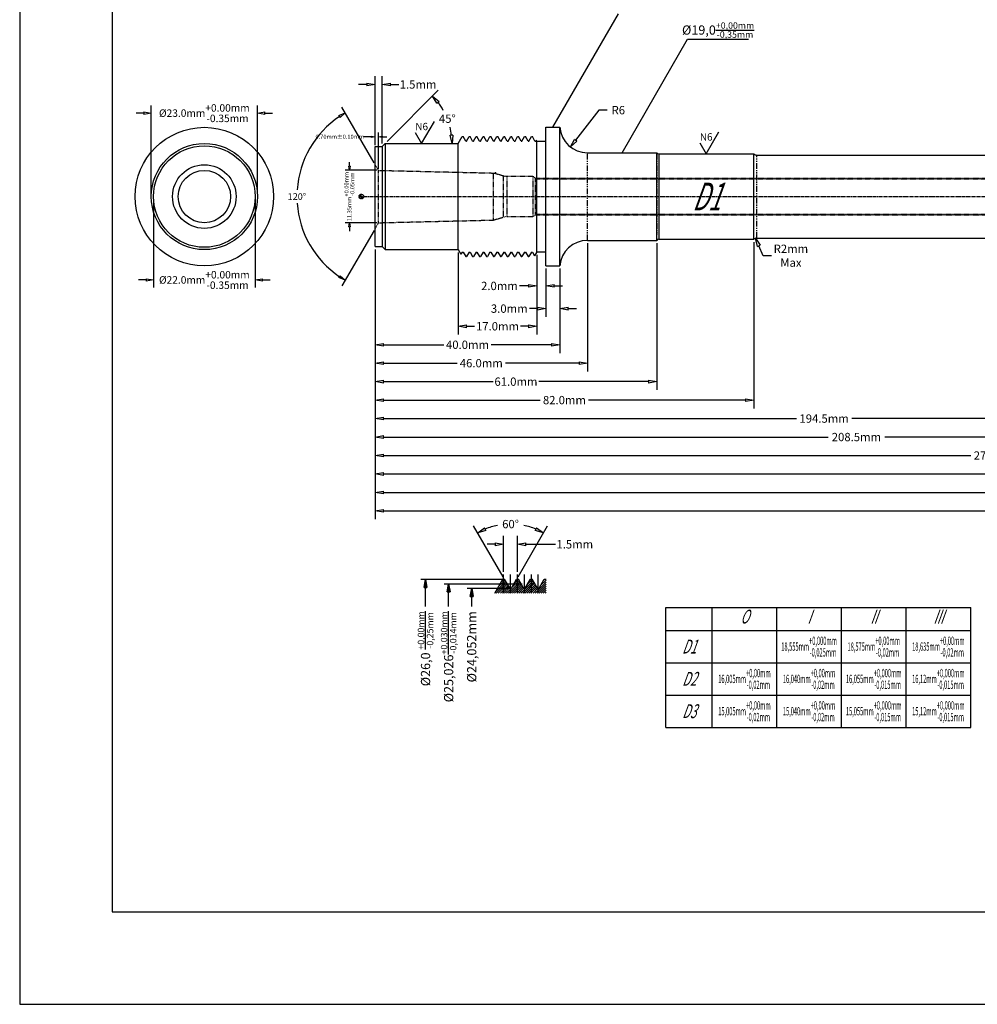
# Model space of a CAD drawing. Units: inches. Extents: x 0 to 594, y 0 to 420.
# Drawn here: x 0 to 207, y 0 to 213 of the extents above; entities that cross this region are included whole.
import ezdxf
from ezdxf.enums import TextEntityAlignment as Align

# ---------------------------------------------------------------- set-up
doc = ezdxf.new("R2010")
doc.units = ezdxf.units.IN
doc.header["$MEASUREMENT"] = 0
for name, pattern in [('CENTER2', [1.125, 0.75, -0.125, 0.125, -0.125]), ('HIDDEN2', [0.1875, 0.125, -0.0625]), ('PHANTOM', [2.5, 1.25, -0.25, 0.25, -0.25, 0.25, -0.25])]:
    doc.linetypes.add(name, pattern=pattern)
for name, color, linetype in [('CENTER', 1, 'CENTER2'), ('CENTERLINE', 1, 'CENTER2'), ('HATCH', 253, 'Continuous'), ('HIDDEN', 5, 'HIDDEN2'), ('PHANTOM', 252, 'PHANTOM'), ('TEXT', 5, 'Continuous')]:
    doc.layers.add(name, color=color, linetype=linetype)
doc.dimstyles.get("Standard").update_dxf_attribs({"dimscale": 10, "dimtxt": 0.18, "dimasz": 0.18, "dimexe": 0.18, "dimexo": 0.0625, "dimgap": 0.09, "dimtad": 0, "dimtih": 1, "dimtoh": 1, "dimdec": 4, "dimzin": 0, "dimdsep": 46, "dimtxsty": 'Standard', "dimblk": 'CLOSEDBLANK', "dimcen": 0.09, "dimadec": 4, "dimazin": 0, "dimtfac": 1, "dimtdec": 4, "dimtofl": 0, "dimtmove": 0, "dimatfit": 3, "dimldrblk": 'CLOSEDBLANK', "dimfxl": 0, "dimtolj": 1, "dimtzin": 0, "dimarcsym": 0})
doc.dimstyles.new('Standard$0', dxfattribs={"dimscale": 10, "dimtxt": 0.18, "dimasz": 0.18, "dimexe": 0.18, "dimexo": 0.0625, "dimgap": 0.09, "dimtad": 0, "dimtih": 1, "dimtoh": 1, "dimdec": 4, "dimzin": 4, "dimdsep": 46, "dimtxsty": 'Standard', "dimblk": 'CLOSEDBLANK', "dimcen": 0.09, "dimadec": 5, "dimazin": 1, "dimtfac": 1, "dimtdec": 4, "dimtofl": 0, "dimtmove": 0, "dimatfit": 3, "dimldrblk": 'CLOSEDBLANK', "dimfxl": 0, "dimtolj": 1, "dimtzin": 0, "dimarcsym": 0})

# ---------------------------------------------------------------- blocks, each defined once
blk = doc.blocks.new('_ClosedBlank')
at = {"color": 0, "linetype": 'ByBlock', "lineweight": -2}
for p, q in [((-1, 0.17), (0, 0)), ((-1, 0.17), (-1, -0.17)), ((0, 0), (-1, -0.17))]:
    blk.add_line(p, q, dxfattribs=at)
blk = doc.blocks.new('*D8')
at = {"color": 0, "lineweight": -2}
for p, q in [((76.1, 187.96), (74.45, 187.96)), ((77, 186.16), (77, 188.86)), ((77.7, 180.99), (77.7, 188.86)), ((78.6, 187.96), (79.5, 187.96))]:
    blk.add_line(p, q, dxfattribs=at)
at = {"layer": 'Defpoints', "color": 0}
for p in [(77.7, 187.96), (77, 185.85), (77.7, 180.68)]:
    blk.add_point(p, dxfattribs=at)
at = {"color": 0, "lineweight": -2, "xscale": 0.8999999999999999, "yscale": 0.8999999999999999, "zscale": 0.8999999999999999}
blk.add_blockref('_ClosedBlank', (77, 187.96), dxfattribs=at)
at = {"color": 0, "lineweight": -2, "xscale": 0.8999999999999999, "yscale": 0.8999999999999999, "zscale": 0.8999999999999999, "rotation": 180}
blk.add_blockref('_ClosedBlank', (77.7, 187.96), dxfattribs=at)
at = {"color": 0, "insert": (69.35, 187.96), "char_height": 0.9, "attachment_point": 5}
blk.add_mtext('\\A1;0.70mm±0.10mm', dxfattribs=at)
blk = doc.blocks.new('*D9')
at = {"color": 0, "lineweight": -2}
for p, q in [((71.42, 181.58), (71.42, 182.48)), ((77.39, 180.68), (70.52, 180.68)), ((77.39, 169.33), (70.52, 169.33)), ((71.42, 168.43), (71.42, 167.53))]:
    blk.add_line(p, q, dxfattribs=at)
at = {"layer": 'Defpoints', "color": 0}
for p in [(71.42, 180.68), (77.7, 180.68), (77.7, 169.33)]:
    blk.add_point(p, dxfattribs=at)
at = {"color": 0, "lineweight": -2, "xscale": 0.8999999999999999, "yscale": 0.8999999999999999, "zscale": 0.8999999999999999}
for p, rotation in [((71.42, 180.68), 270), ((71.42, 169.33), 90)]:
    blk.add_blockref('_ClosedBlank', p, dxfattribs=dict(at, rotation=rotation))
at = {"color": 0, "insert": (71.42, 175), "char_height": 0.9, "attachment_point": 5, "rotation": 90}
blk.add_mtext('\\A1;11.35mm\\S+0.00mm^ -0.05mm;', dxfattribs=at)
blk = doc.blocks.new('*D10')
at = {"color": 0, "lineweight": -2}
for p, q in [((76.75, 182.32), (69.79, 194.37)), ((76.75, 167.68), (69.79, 155.63))]:
    blk.add_line(p, q, dxfattribs=at)
for start, end in [(123.9431, 176.0546), (183.9454, 236.0569)]:
    blk.add_arc((80.98, 175), 20.93, start, end, dxfattribs=at)
at = {"layer": 'Defpoints', "color": 0}
for p in [(61.31, 182.16), (77, 181.89), (77.7, 180.68), (77.7, 169.33), (77, 168.11)]:
    blk.add_point(p, dxfattribs=at)
at = {"color": 0, "lineweight": -2, "xscale": 1.44, "yscale": 1.44, "zscale": 1.44}
for p, rotation in [((70.51, 193.12), 31.97154143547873), ((70.51, 156.88), 328.0284585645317)]:
    blk.add_blockref('_ClosedBlank', p, dxfattribs=dict(at, rotation=rotation))
at = {"color": 0, "insert": (60.05, 175), "char_height": 1.44, "attachment_point": 5}
blk.add_mtext('\\A1;120°', dxfattribs=at)
blk = doc.blocks.new('*D14')
at = {"color": 0, "lineweight": -2}
for p, q in [((77, 186.48), (77, 201.08)), ((78.5, 186.48), (78.5, 201.08)), ((75.2, 199.28), (73.4, 199.28)), ((80.3, 199.28), (82.1, 199.28))]:
    blk.add_line(p, q, dxfattribs=at)
at = {"layer": 'Defpoints', "color": 0}
for p in [(78.5, 199.28), (77, 185.85), (78.5, 185.85)]:
    blk.add_point(p, dxfattribs=at)
at = {"color": 0, "lineweight": -2, "xscale": 1.8, "yscale": 1.8, "zscale": 1.8}
blk.add_blockref('_ClosedBlank', (77, 199.28), dxfattribs=at)
at = {"color": 0, "lineweight": -2, "xscale": 1.8, "yscale": 1.8, "zscale": 1.8, "rotation": 180}
blk.add_blockref('_ClosedBlank', (78.5, 199.28), dxfattribs=at)
at = {"color": 0, "insert": (86.3, 199.28), "char_height": 1.8, "attachment_point": 5}
blk.add_mtext('\\A1;1.5mm', dxfattribs=at)
blk = doc.blocks.new('*D15')
at = {"color": 0, "lineweight": -2}
blk.add_line((79.59, 186.94), (90.68, 198.03), dxfattribs=at)
for start, end in [(29.5981, 37.8873), (7.1127, 14.2286)]:
    blk.add_arc((79.15, 186.5), 14.51, start, end, dxfattribs=at)
at = {"layer": 'Defpoints', "color": 0}
for p in [(91.72, 193.75), (78.5, 185.85), (79.15, 186.5), (79.15, 186.5), (95, 186.5)]:
    blk.add_point(p, dxfattribs=at)
at = {"color": 0, "lineweight": -2, "xscale": 1.8, "yscale": 1.8, "zscale": 1.8}
for p, rotation in [((89.41, 196.76), 131.443631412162), ((93.66, 186.5), 273.5563685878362)]:
    blk.add_blockref('_ClosedBlank', p, dxfattribs=dict(at, rotation=rotation))
at = {"color": 0, "insert": (92.63, 191.87), "char_height": 1.8, "attachment_point": 5}
blk.add_mtext('\\A1;45°', dxfattribs=at)
blk = doc.blocks.new('*D29')
at = {"color": 0, "lineweight": -2}
for p, q in [((125.47, 193.72), (120.41, 187.18)), ((127.27, 193.72), (125.47, 193.72))]:
    blk.add_line(p, q, dxfattribs=at)
at = {"layer": 'Defpoints', "color": 0}
for p in [(122.98, 190.5), (119.31, 185.75)]:
    blk.add_point(p, dxfattribs=at)
at = {"color": 0, "lineweight": -2, "xscale": 1.8, "yscale": 1.8, "zscale": 1.8, "rotation": 232.3171928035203}
blk.add_blockref('_ClosedBlank', (119.31, 185.75), dxfattribs=at)
at = {"color": 0, "insert": (129.67, 193.72), "char_height": 1.8, "attachment_point": 5}
blk.add_mtext('\\A1;R6', dxfattribs=at)
blk = doc.blocks.new('*D31')
at = {"color": 0, "lineweight": -2}
for p, q in [((77, 163.53), (77, 141.09)), ((117, 155.38), (117, 141.09)), ((78.8, 142.89), (91.9, 142.89)), ((115.2, 142.89), (102.1, 142.89))]:
    blk.add_line(p, q, dxfattribs=at)
at = {"layer": 'Defpoints', "color": 0}
for p in [(77, 164.15), (117, 156), (117, 142.89)]:
    blk.add_point(p, dxfattribs=at)
at = {"color": 0, "lineweight": -2, "xscale": 1.8, "yscale": 1.8, "zscale": 1.8, "rotation": 180}
blk.add_blockref('_ClosedBlank', (77, 142.89), dxfattribs=at)
at = {"color": 0, "lineweight": -2, "xscale": 1.8, "yscale": 1.8, "zscale": 1.8}
blk.add_blockref('_ClosedBlank', (117, 142.89), dxfattribs=at)
at = {"color": 0, "insert": (97, 142.89), "char_height": 1.8, "attachment_point": 5}
blk.add_mtext('\\A1;40.0mm', dxfattribs=at)
blk = doc.blocks.new('*D32')
at = {"color": 0, "lineweight": -2}
for p, q in [((122.98, 164.88), (122.98, 137.1)), ((77, 163.53), (77, 137.1)), ((78.8, 138.9), (94.74, 138.9)), ((121.18, 138.9), (105.24, 138.9))]:
    blk.add_line(p, q, dxfattribs=at)
at = {"layer": 'Defpoints', "color": 0}
for p in [(122.98, 165.5), (77, 164.15), (77, 138.9)]:
    blk.add_point(p, dxfattribs=at)
at = {"color": 0, "lineweight": -2, "xscale": 1.8, "yscale": 1.8, "zscale": 1.8, "rotation": 180}
blk.add_blockref('_ClosedBlank', (77, 138.9), dxfattribs=at)
at = {"color": 0, "lineweight": -2, "xscale": 1.8, "yscale": 1.8, "zscale": 1.8}
blk.add_blockref('_ClosedBlank', (122.98, 138.9), dxfattribs=at)
at = {"color": 0, "insert": (99.99, 138.9), "char_height": 1.8, "attachment_point": 5}
blk.add_mtext('\\A1;46.0mm', dxfattribs=at)
blk = doc.blocks.new('*D33')
at = {"color": 0, "lineweight": -2}
for p, q in [((138, 164.88), (138, 133.1)), ((77, 163.53), (77, 133.1)), ((78.8, 134.9), (102.55, 134.9)), ((136.2, 134.9), (112.45, 134.9))]:
    blk.add_line(p, q, dxfattribs=at)
at = {"layer": 'Defpoints', "color": 0}
for p in [(138, 165.5), (77, 164.15), (77, 134.9)]:
    blk.add_point(p, dxfattribs=at)
at = {"color": 0, "lineweight": -2, "xscale": 1.8, "yscale": 1.8, "zscale": 1.8, "rotation": 180}
blk.add_blockref('_ClosedBlank', (77, 134.9), dxfattribs=at)
at = {"color": 0, "lineweight": -2, "xscale": 1.8, "yscale": 1.8, "zscale": 1.8}
blk.add_blockref('_ClosedBlank', (138, 134.9), dxfattribs=at)
at = {"color": 0, "insert": (107.5, 134.9), "char_height": 1.8, "attachment_point": 5}
blk.add_mtext('\\A1;61.0mm', dxfattribs=at)
blk = doc.blocks.new('*D34')
at = {"color": 0, "lineweight": -2}
for p, q in [((159, 165.13), (159, 129.1)), ((77, 163.53), (77, 129.1)), ((78.8, 130.9), (112.75, 130.9)), ((157.2, 130.9), (123.25, 130.9))]:
    blk.add_line(p, q, dxfattribs=at)
at = {"layer": 'Defpoints', "color": 0}
for p in [(159, 165.75), (77, 164.15), (77, 130.9)]:
    blk.add_point(p, dxfattribs=at)
at = {"color": 0, "lineweight": -2, "xscale": 1.8, "yscale": 1.8, "zscale": 1.8, "rotation": 180}
blk.add_blockref('_ClosedBlank', (77, 130.9), dxfattribs=at)
at = {"color": 0, "lineweight": -2, "xscale": 1.8, "yscale": 1.8, "zscale": 1.8}
blk.add_blockref('_ClosedBlank', (159, 130.9), dxfattribs=at)
at = {"color": 0, "insert": (118, 130.9), "char_height": 1.8, "attachment_point": 5}
blk.add_mtext('\\A1;82.0mm', dxfattribs=at)
blk = doc.blocks.new('*D35')
at = {"color": 0, "lineweight": -2}
for p, q in [((271.5, 165.38), (271.5, 125.1)), ((77, 163.53), (77, 125.1)), ((78.8, 126.9), (168.25, 126.9)), ((269.7, 126.9), (180.25, 126.9))]:
    blk.add_line(p, q, dxfattribs=at)
at = {"layer": 'Defpoints', "color": 0}
for p in [(271.5, 166), (77, 164.15), (77, 126.9)]:
    blk.add_point(p, dxfattribs=at)
at = {"color": 0, "lineweight": -2, "xscale": 1.8, "yscale": 1.8, "zscale": 1.8, "rotation": 180}
blk.add_blockref('_ClosedBlank', (77, 126.9), dxfattribs=at)
at = {"color": 0, "lineweight": -2, "xscale": 1.8, "yscale": 1.8, "zscale": 1.8}
blk.add_blockref('_ClosedBlank', (271.5, 126.9), dxfattribs=at)
at = {"color": 0, "insert": (174.25, 126.9), "char_height": 1.8, "attachment_point": 5}
blk.add_mtext('\\A1;194.5mm', dxfattribs=at)
blk = doc.blocks.new('*D36')
at = {"color": 0, "lineweight": -2}
for p, q in [((285.5, 165.39), (285.5, 121.1)), ((77, 163.53), (77, 121.1)), ((78.8, 122.9), (175.1, 122.9)), ((283.7, 122.9), (187.4, 122.9))]:
    blk.add_line(p, q, dxfattribs=at)
at = {"layer": 'Defpoints', "color": 0}
for p in [(285.5, 166.01), (77, 164.15), (77, 122.9)]:
    blk.add_point(p, dxfattribs=at)
at = {"color": 0, "lineweight": -2, "xscale": 1.8, "yscale": 1.8, "zscale": 1.8, "rotation": 180}
blk.add_blockref('_ClosedBlank', (77, 122.9), dxfattribs=at)
at = {"color": 0, "lineweight": -2, "xscale": 1.8, "yscale": 1.8, "zscale": 1.8}
blk.add_blockref('_ClosedBlank', (285.5, 122.9), dxfattribs=at)
at = {"color": 0, "insert": (181.25, 122.9), "char_height": 1.8, "attachment_point": 5}
blk.add_mtext('\\A1;208.5mm', dxfattribs=at)
blk = doc.blocks.new('*D37')
at = {"color": 0, "lineweight": -2}
for p, q in [((347, 166.13), (347, 117.1)), ((77, 163.53), (77, 117.1)), ((78.8, 118.9), (206, 118.9)), ((345.2, 118.9), (218, 118.9))]:
    blk.add_line(p, q, dxfattribs=at)
at = {"layer": 'Defpoints', "color": 0}
for p in [(347, 166.75), (77, 164.15), (77, 118.9)]:
    blk.add_point(p, dxfattribs=at)
at = {"color": 0, "lineweight": -2, "xscale": 1.8, "yscale": 1.8, "zscale": 1.8, "rotation": 180}
blk.add_blockref('_ClosedBlank', (77, 118.9), dxfattribs=at)
at = {"color": 0, "lineweight": -2, "xscale": 1.8, "yscale": 1.8, "zscale": 1.8}
blk.add_blockref('_ClosedBlank', (347, 118.9), dxfattribs=at)
at = {"color": 0, "insert": (212, 118.9), "char_height": 1.8, "attachment_point": 5}
blk.add_mtext('\\A1;270.0mm', dxfattribs=at)
blk = doc.blocks.new('*D38')
at = {"color": 0, "lineweight": -2}
for p, q in [((385, 166.38), (385, 113.1)), ((77, 163.53), (77, 113.1)), ((78.8, 114.9), (225, 114.9)), ((383.2, 114.9), (237, 114.9))]:
    blk.add_line(p, q, dxfattribs=at)
at = {"layer": 'Defpoints', "color": 0}
for p in [(385, 167), (77, 164.15), (77, 114.9)]:
    blk.add_point(p, dxfattribs=at)
at = {"color": 0, "lineweight": -2, "xscale": 1.8, "yscale": 1.8, "zscale": 1.8, "rotation": 180}
blk.add_blockref('_ClosedBlank', (77, 114.9), dxfattribs=at)
at = {"color": 0, "lineweight": -2, "xscale": 1.8, "yscale": 1.8, "zscale": 1.8}
blk.add_blockref('_ClosedBlank', (385, 114.9), dxfattribs=at)
at = {"color": 0, "insert": (231, 114.9), "char_height": 1.8, "attachment_point": 5}
blk.add_mtext('\\A1;308.0mm', dxfattribs=at)
blk = doc.blocks.new('*D39')
at = {"color": 0, "lineweight": -2}
for p, q in [((445, 166.68), (445, 109.1)), ((77, 163.53), (77, 109.1)), ((78.8, 110.9), (254.85, 110.9)), ((443.2, 110.9), (267.15, 110.9))]:
    blk.add_line(p, q, dxfattribs=at)
at = {"layer": 'Defpoints', "color": 0}
for p in [(445, 167.3), (77, 164.15), (77, 110.9)]:
    blk.add_point(p, dxfattribs=at)
at = {"color": 0, "lineweight": -2, "xscale": 1.8, "yscale": 1.8, "zscale": 1.8, "rotation": 180}
blk.add_blockref('_ClosedBlank', (77, 110.9), dxfattribs=at)
at = {"color": 0, "lineweight": -2, "xscale": 1.8, "yscale": 1.8, "zscale": 1.8}
blk.add_blockref('_ClosedBlank', (445, 110.9), dxfattribs=at)
at = {"color": 0, "insert": (261, 110.9), "char_height": 1.8, "attachment_point": 5}
blk.add_mtext('\\A1;368.0mm', dxfattribs=at)
blk = doc.blocks.new('*D40')
at = {"color": 0, "lineweight": -2}
for p, q in [((114, 159.38), (114, 148.92)), ((117, 159.38), (117, 148.92)), ((112.2, 150.72), (110.4, 150.72)), ((118.8, 150.72), (120.6, 150.72))]:
    blk.add_line(p, q, dxfattribs=at)
at = {"layer": 'Defpoints', "color": 0}
for p in [(114, 160), (117, 160), (117, 150.72)]:
    blk.add_point(p, dxfattribs=at)
at = {"color": 0, "lineweight": -2, "xscale": 1.8, "yscale": 1.8, "zscale": 1.8}
blk.add_blockref('_ClosedBlank', (114, 150.72), dxfattribs=at)
at = {"color": 0, "lineweight": -2, "xscale": 1.8, "yscale": 1.8, "zscale": 1.8, "rotation": 180}
blk.add_blockref('_ClosedBlank', (117, 150.72), dxfattribs=at)
at = {"color": 0, "insert": (106.05, 150.72), "char_height": 1.8, "attachment_point": 5}
blk.add_mtext('\\A1;3.0mm', dxfattribs=at)
blk = doc.blocks.new('*D41')
at = {"color": 0, "lineweight": -2}
for p, q in [((492, 168.13), (492, 105.1)), ((77, 163.53), (77, 105.1)), ((78.8, 106.9), (278.65, 106.9)), ((490.2, 106.9), (290.35, 106.9))]:
    blk.add_line(p, q, dxfattribs=at)
at = {"layer": 'Defpoints', "color": 0}
for p in [(492, 168.75), (77, 164.15), (77, 106.9)]:
    blk.add_point(p, dxfattribs=at)
at = {"color": 0, "lineweight": -2, "xscale": 1.8, "yscale": 1.8, "zscale": 1.8, "rotation": 180}
blk.add_blockref('_ClosedBlank', (77, 106.9), dxfattribs=at)
at = {"color": 0, "lineweight": -2, "xscale": 1.8, "yscale": 1.8, "zscale": 1.8}
blk.add_blockref('_ClosedBlank', (492, 106.9), dxfattribs=at)
at = {"color": 0, "insert": (284.5, 106.9), "char_height": 1.8, "attachment_point": 5}
blk.add_mtext('\\A1;415.0mm', dxfattribs=at)
blk = doc.blocks.new('*D42')
at = {"color": 0, "lineweight": -2}
for p, q in [((112, 162.38), (112, 153.84)), ((114, 159.38), (114, 153.84)), ((110.2, 155.64), (108.27, 155.64)), ((115.8, 155.64), (117.6, 155.64))]:
    blk.add_line(p, q, dxfattribs=at)
at = {"layer": 'Defpoints', "color": 0}
for p in [(112, 163), (114, 160), (114, 155.64)]:
    blk.add_point(p, dxfattribs=at)
at = {"color": 0, "lineweight": -2, "xscale": 1.8, "yscale": 1.8, "zscale": 1.8}
blk.add_blockref('_ClosedBlank', (112, 155.64), dxfattribs=at)
at = {"color": 0, "lineweight": -2, "xscale": 1.8, "yscale": 1.8, "zscale": 1.8, "rotation": 180}
blk.add_blockref('_ClosedBlank', (114, 155.64), dxfattribs=at)
at = {"color": 0, "insert": (103.92, 155.64), "char_height": 1.8, "attachment_point": 5}
blk.add_mtext('\\A1;2.0mm', dxfattribs=at)
blk = doc.blocks.new('*D43')
at = {"color": 0, "lineweight": -2}
for p, q in [((95, 162.88), (95, 145.09)), ((112, 162.38), (112, 145.09)), ((96.8, 146.89), (98.55, 146.89)), ((110.2, 146.89), (108.45, 146.89))]:
    blk.add_line(p, q, dxfattribs=at)
at = {"layer": 'Defpoints', "color": 0}
for p in [(95, 163.5), (112, 163), (112, 146.89)]:
    blk.add_point(p, dxfattribs=at)
at = {"color": 0, "lineweight": -2, "xscale": 1.8, "yscale": 1.8, "zscale": 1.8, "rotation": 180}
blk.add_blockref('_ClosedBlank', (95, 146.89), dxfattribs=at)
at = {"color": 0, "lineweight": -2, "xscale": 1.8, "yscale": 1.8, "zscale": 1.8}
blk.add_blockref('_ClosedBlank', (112, 146.89), dxfattribs=at)
at = {"color": 0, "insert": (103.5, 146.89), "char_height": 1.8, "attachment_point": 5}
blk.add_mtext('\\A1;17.0mm', dxfattribs=at)
blk = doc.blocks.new('*D44')
at = {"color": 0, "lineweight": -2}
for p, q in [((161.06, 162.18), (160.1, 164.31)), ((162.86, 162.18), (161.06, 162.18))]:
    blk.add_line(p, q, dxfattribs=at)
at = {"layer": 'Defpoints', "color": 0}
for p in [(159.36, 165.95), (160.18, 164.13)]:
    blk.add_point(p, dxfattribs=at)
at = {"color": 0, "lineweight": -2, "xscale": 1.8, "yscale": 1.8, "zscale": 1.8, "rotation": 114.356826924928}
blk.add_blockref('_ClosedBlank', (159.36, 165.95), dxfattribs=at)
at = {"color": 0, "insert": (167.06, 162.18), "char_height": 1.8, "attachment_point": 5}
blk.add_mtext('\\A1;R2mm\\PMax', dxfattribs=at)
blk = doc.blocks.new('*D57')
at = {"color": 0, "lineweight": -2}
for p, q in [((29, 174.44), (29, 155.31)), ((51, 174.44), (51, 155.31)), ((27.38, 156.93), (25.76, 156.93)), ((52.62, 156.93), (54.24, 156.93))]:
    blk.add_line(p, q, dxfattribs=at)
at = {"layer": 'Defpoints', "color": 0}
for p in [(29, 175), (51, 175), (51, 156.93)]:
    blk.add_point(p, dxfattribs=at)
at = {"color": 0, "lineweight": -2, "xscale": 1.62, "yscale": 1.62, "zscale": 1.62}
blk.add_blockref('_ClosedBlank', (29, 156.93), dxfattribs=at)
at = {"color": 0, "lineweight": -2, "xscale": 1.62, "yscale": 1.62, "zscale": 1.62, "rotation": 180}
blk.add_blockref('_ClosedBlank', (51, 156.93), dxfattribs=at)
at = {"color": 0, "insert": (40, 156.93), "char_height": 1.62, "attachment_point": 5}
blk.add_mtext('\\A1;%%C22.0mm\\S+0.00mm^ -0.35mm;', dxfattribs=at)
blk = doc.blocks.new('*D58')
at = {"color": 0, "lineweight": -2}
for p, q in [((28.5, 175.56), (28.5, 194.69)), ((51.5, 175.56), (51.5, 194.69)), ((26.88, 193.07), (25.26, 193.07)), ((53.12, 193.07), (54.74, 193.07))]:
    blk.add_line(p, q, dxfattribs=at)
at = {"layer": 'Defpoints', "color": 0}
for p in [(51.5, 193.07), (28.5, 175), (51.5, 175)]:
    blk.add_point(p, dxfattribs=at)
at = {"color": 0, "lineweight": -2, "xscale": 1.62, "yscale": 1.62, "zscale": 1.62}
blk.add_blockref('_ClosedBlank', (28.5, 193.07), dxfattribs=at)
at = {"color": 0, "lineweight": -2, "xscale": 1.62, "yscale": 1.62, "zscale": 1.62, "rotation": 180}
blk.add_blockref('_ClosedBlank', (51.5, 193.07), dxfattribs=at)
at = {"color": 0, "insert": (40, 193.07), "char_height": 1.62, "attachment_point": 5}
blk.add_mtext('\\A1;%%C23.0mm\\S+0.00mm^ -0.35mm;', dxfattribs=at)
blk = doc.blocks.new('*D59')
at = {"color": 0, "lineweight": -2}
for p, q in [((104.83, 93.72), (104.83, 101.46)), ((107.83, 93.72), (107.83, 101.46)), ((103.03, 99.66), (101.23, 99.66)), ((109.63, 99.66), (116.04, 99.66))]:
    blk.add_line(p, q, dxfattribs=at)
at = {"layer": 'Defpoints', "color": 0}
for p in [(107.83, 99.66), (104.83, 93.1), (107.83, 93.1)]:
    blk.add_point(p, dxfattribs=at)
at = {"color": 0, "lineweight": -2, "xscale": 1.8, "yscale": 1.8, "zscale": 1.8}
blk.add_blockref('_ClosedBlank', (104.83, 99.66), dxfattribs=at)
at = {"color": 0, "lineweight": -2, "xscale": 1.8, "yscale": 1.8, "zscale": 1.8, "rotation": 180}
blk.add_blockref('_ClosedBlank', (107.83, 99.66), dxfattribs=at)
at = {"color": 0, "insert": (120.24, 99.66), "char_height": 1.8, "attachment_point": 5}
blk.add_mtext('\\A1;1.5mm', dxfattribs=at)
blk = doc.blocks.new('*D60')
at = {"color": 0, "lineweight": -2}
for p, q in [((104.71, 92.64), (98.33, 103.69)), ((107.96, 92.64), (114.34, 103.69))]:
    blk.add_line(p, q, dxfattribs=at)
for start, end in [(101.5653, 112.7402), (67.2598, 78.4347)]:
    blk.add_arc((106.33, 89.83), 14.22, start, end, dxfattribs=at)
at = {"layer": 'Defpoints', "color": 0}
for p in [(108.8, 103.82), (105.02, 92.1), (107.65, 92.1), (106.15, 90.15), (106.52, 90.15)]:
    blk.add_point(p, dxfattribs=at)
at = {"color": 0, "lineweight": -2, "xscale": 1.8, "yscale": 1.8, "zscale": 1.8}
for p, rotation in [((99.23, 102.14), 206.3701175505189), ((113.44, 102.14), 333.6298824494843)]:
    blk.add_blockref('_ClosedBlank', p, dxfattribs=dict(at, rotation=rotation))
at = {"color": 0, "insert": (106.33, 104.04), "char_height": 1.8, "attachment_point": 5}
blk.add_mtext('\\A1;60°', dxfattribs=at)

msp = doc.modelspace()

# ---------------------------------------------------------------- hatches: boundary and pattern name
for points in [[(87.91514, 92.09842), (87.61514, 90.29842), (88.21514, 90.29842)], [(92.91514, 91.12742), (92.61514, 89.32742), (93.21514, 89.32742)], [(97.91514, 90.15042), (97.61514, 88.35042), (98.21514, 88.35042)]]:
    msp.add_hatch(color=256).paths.add_polyline_path(points)
at = {"layer": 'CENTER'}
h = msp.add_hatch(dxfattribs=at)
h.set_pattern_fill('ANSI31', color=256, style=0)
h.set_pattern_definition([(45, (22, 125), (-0.08838835, 0.08838835), [])])
h.paths.add_polyline_path([(74.49996, 175.00003), (73.99996, 175.00003), (73.99996, 174.50003, 0.414213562)])
h.paths.add_polyline_path([(73.99996, 175.50003, 0.414213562), (73.49996, 175.00003), (73.99996, 175.00003)])
at = {"layer": 'HATCH'}
h = msp.add_hatch(dxfattribs=at)
h.set_pattern_fill('ANSI31', color=256, scale=2.5, style=0)
h.set_pattern_definition([(45, (20, 20), (-0.2209709, 0.2209709), [])])
h.paths.add_polyline_path([(104.83469, 92.09842), (104.64719, 92.09842), (104.08658, 91.12742), (104.83469, 91.12742)])
h.paths.add_polyline_path([(105.02219, 92.09842), (104.83469, 92.09842), (104.83469, 91.12742), (105.58279, 91.12742)])
h.paths.add_polyline_path([(105.58279, 91.12742), (104.83469, 91.12742), (104.83469, 90.15042), (106.14687, 90.15042)])
h.paths.add_polyline_path([(104.83469, 91.12742), (104.08658, 91.12742), (103.52251, 90.15042), (104.83469, 90.15042)])
h.paths.add_polyline_path([(104.83469, 90.15042), (103.52251, 90.15042), (102.91514, 89.09842), (104.83469, 89.09842)])
h.paths.add_polyline_path([(106.33469, 90.14987), (106.14719, 90.14987), (106.14687, 90.15042), (104.83469, 90.15042), (104.83469, 89.09842), (106.33469, 89.09842)])
h.paths.add_polyline_path([(107.83469, 91.12742), (107.08658, 91.12742), (106.52219, 90.14987), (106.33469, 90.14987), (106.33469, 89.09842), (107.83469, 89.09842)])
h.paths.add_polyline_path([(107.83469, 92.09842), (107.64719, 92.09842), (107.08658, 91.12742), (107.83469, 91.12742)])
h.paths.add_polyline_path([(108.02219, 92.09842), (107.83469, 92.09842), (107.83469, 91.12742), (108.58279, 91.12742)])
h.paths.add_polyline_path([(108.58279, 91.12742), (107.83469, 91.12742), (107.83469, 89.09842), (109.33469, 89.09842), (109.33469, 90.14987), (109.14719, 90.14987)])
h.paths.add_polyline_path([(110.83469, 92.09842), (110.64719, 92.09842), (109.52219, 90.14987), (109.33469, 90.14987), (109.33469, 89.09842), (110.83469, 89.09842)])
h.paths.add_polyline_path([(112.33469, 90.14987), (112.14719, 90.14987), (111.02219, 92.09842), (110.83469, 92.09842), (110.83469, 89.09842), (112.33469, 89.09842)])
h.paths.add_polyline_path([(114.02219, 92.09842), (113.64719, 92.09842), (112.52219, 90.14987), (112.33469, 90.14987), (112.33469, 89.09842), (114.02219, 89.09842)])

# ---------------------------------------------------------------- linework, layer by layer
for p, q in [((115.49996, 190.00003), (129.68855, 214.57538)), ((130.48952, 184.50003), (144.67811, 209.07538)), ((144.67811, 209.07538), (157.89967, 209.07538)), ((87.07496, 186.50003), (89.82459, 191.26253)), ((113.99996, 160.00003), (113.99996, 190.00003)), ((113.99996, 190.00003), (116.99996, 190.00003)), ((116.99996, 160.00003), (116.99996, 190.00003)), ((85.70014, 188.88128), (87.07496, 186.50003)), ((94.99996, 186.50003), (95.86599, 188.00003)), ((95.86599, 188.00003), (96.05349, 188.00003)), ((96.61599, 187.02575), (96.05349, 188.00003)), ((96.80349, 187.02575), (97.36599, 188.00003)), ((97.36599, 188.00003), (97.55349, 188.00003)), ((98.11599, 187.02575), (97.55349, 188.00003)), ((98.30349, 187.02575), (98.86599, 188.00003)), ((98.86599, 188.00003), (99.05349, 188.00003)), ((99.61599, 187.02575), (99.05349, 188.00003)), ((99.80349, 187.02575), (100.36599, 188.00003)), ((100.36599, 188.00003), (100.55349, 188.00003)), ((101.11599, 187.02575), (100.55349, 188.00003)), ((101.30349, 187.02575), (101.86599, 188.00003)), ((101.86599, 188.00003), (102.05349, 188.00003)), ((102.61599, 187.02575), (102.05349, 188.00003)), ((102.80349, 187.02575), (103.36599, 188.00003)), ((103.36599, 188.00003), (103.55349, 188.00003)), ((104.11599, 187.02575), (103.55349, 188.00003)), ((104.30349, 187.02575), (104.86599, 188.00003)), ((104.86599, 188.00003), (105.05349, 188.00003)), ((105.61599, 187.02575), (105.05349, 188.00003)), ((105.80349, 187.02575), (106.36599, 188.00003)), ((106.36599, 188.00003), (106.55349, 188.00003)), ((107.11599, 187.02575), (106.55349, 188.00003)), ((107.30349, 187.02575), (107.86599, 188.00003)), ((107.86599, 188.00003), (108.05349, 188.00003)), ((108.61599, 187.02575), (108.05349, 188.00003)), ((108.80349, 187.02575), (109.36599, 188.00003)), ((109.36599, 188.00003), (109.55349, 188.00003)), ((110.11599, 187.02575), (109.55349, 188.00003)), ((110.30349, 187.02575), (110.86599, 188.00003)), ((110.86599, 188.00003), (111.05349, 188.00003)), ((111.61599, 187.02575), (111.05349, 188.00003)), ((148.71647, 184.25003), (151.4661, 189.01253)), ((76.99996, 185.85003), (78.49996, 185.85003)), ((76.99996, 164.15003), (76.99996, 185.85003)), ((78.49996, 185.85003), (79.14996, 186.50003)), ((78.49996, 185.85003), (78.49996, 164.15003)), ((79.14996, 186.50003), (79.14996, 163.50003)), ((79.14996, 186.50003), (94.99996, 186.50003)), ((91.99996, 186.50003), (94.99996, 186.50003)), ((94.99996, 163.46503), (94.99996, 186.50003)), ((94.99996, 163.50003), (94.99996, 186.50003)), ((96.61599, 187.02575), (96.80349, 187.02575)), ((98.11599, 187.02575), (98.30349, 187.02575)), ((99.61599, 187.02575), (99.80349, 187.02575)), ((101.11599, 187.02575), (101.30349, 187.02575)), ((102.61599, 187.02575), (102.80349, 187.02575)), ((104.11599, 187.02575), (104.30349, 187.02575)), ((105.61599, 187.02575), (105.80349, 187.02575)), ((107.11599, 187.02575), (107.30349, 187.02575)), ((108.61599, 187.02575), (108.80349, 187.02575)), ((110.11599, 187.02575), (110.30349, 187.02575)), ((111.61599, 187.02575), (111.80349, 187.02575)), ((111.80349, 187.02575), (111.8943, 187.18304)), ((111.99996, 187.00003), (111.8943, 187.18304)), ((111.99996, 163.00003), (111.99996, 187.00003)), ((111.99996, 187.00003), (113.99996, 187.00003)), ((147.34165, 186.63128), (148.71647, 184.25003)), ((122.97909, 184.50003), (137.99996, 184.50003)), ((137.99996, 165.50003), (137.99996, 184.50003)), ((138.43297, 184.25003), (158.99996, 184.25003)), ((138.43297, 184.25003), (138.43297, 165.75003)), ((158.99996, 165.75003), (158.99996, 184.25003)), ((159.6614, 184.00003), (271.49996, 184.00003)), ((122.97909, 165.50003), (137.99996, 165.50003)), ((138.43297, 165.75003), (158.99996, 165.75003)), ((159.6614, 166.00003), (271.49996, 166.00003)), ((76.99996, 164.15003), (78.49996, 164.15003)), ((78.49996, 164.15003), (79.14996, 163.50003)), ((79.14996, 163.50003), (94.99996, 163.50003)), ((91.99996, 163.50003), (94.99996, 163.50003)), ((94.99996, 163.50003), (95.58474, 162.48717)), ((95.86599, 162.97431), (95.58474, 162.48717)), ((95.86599, 162.97431), (96.05349, 162.97431)), ((96.05349, 162.97431), (96.61599, 162.00003)), ((97.36599, 162.97431), (96.80349, 162.00003)), ((97.36599, 162.97431), (97.55349, 162.97431)), ((97.55349, 162.97431), (98.11599, 162.00003)), ((98.86599, 162.97431), (98.30349, 162.00003)), ((98.86599, 162.97431), (99.05349, 162.97431)), ((99.05349, 162.97431), (99.61599, 162.00003)), ((100.36599, 162.97431), (99.80349, 162.00003)), ((100.36599, 162.97431), (100.55349, 162.97431)), ((100.55349, 162.97431), (101.11599, 162.00003)), ((101.86599, 162.97431), (101.30349, 162.00003)), ((101.86599, 162.97431), (102.05349, 162.97431)), ((102.05349, 162.97431), (102.61599, 162.00003)), ((103.36599, 162.97431), (102.80349, 162.00003)), ((103.36599, 162.97431), (103.55349, 162.97431)), ((103.55349, 162.97431), (104.11599, 162.00003)), ((104.86599, 162.97431), (104.30349, 162.00003)), ((104.86599, 162.97431), (105.05349, 162.97431)), ((105.05349, 162.97431), (105.61599, 162.00003)), ((106.36599, 162.97431), (105.80349, 162.00003)), ((106.36599, 162.97431), (106.55349, 162.97431)), ((106.55349, 162.97431), (107.11599, 162.00003)), ((107.86599, 162.97431), (107.30349, 162.00003)), ((107.86599, 162.97431), (108.05349, 162.97431)), ((108.05349, 162.97431), (108.61599, 162.00003)), ((109.36599, 162.97431), (108.80349, 162.00003)), ((109.36599, 162.97431), (109.55349, 162.97431)), ((109.55349, 162.97431), (110.11599, 162.00003)), ((110.86599, 162.97431), (110.30349, 162.00003)), ((110.86599, 162.97431), (111.05349, 162.97431)), ((111.05349, 162.97431), (111.5193, 162.1675)), ((111.99996, 163.00003), (111.5193, 162.1675)), ((111.99996, 163.00003), (113.99996, 163.00003)), ((96.61599, 162.00003), (96.80349, 162.00003)), ((98.11599, 162.00003), (98.30349, 162.00003)), ((99.61599, 162.00003), (99.80349, 162.00003)), ((101.11599, 162.00003), (101.30349, 162.00003)), ((102.61599, 162.00003), (102.80349, 162.00003)), ((104.11599, 162.00003), (104.30349, 162.00003)), ((105.61599, 162.00003), (105.80349, 162.00003)), ((107.11599, 162.00003), (107.30349, 162.00003)), ((108.61599, 162.00003), (108.80349, 162.00003)), ((110.11599, 162.00003), (110.30349, 162.00003)), ((113.99996, 160.00003), (116.99996, 160.00003)), ((86.91514, 92.09842), (104.64719, 92.09842)), ((87.91514, 86.15042), (87.91514, 92.09842)), ((102.91514, 89.09842), (104.64719, 92.09842)), ((104.64719, 92.09842), (105.02219, 92.09842)), ((104.83469, 89.09842), (104.83469, 93.09842)), ((106.14719, 90.14987), (105.02219, 92.09842)), ((106.33469, 89.09842), (106.33469, 93.09842)), ((106.52219, 90.14987), (107.64719, 92.09842)), ((107.64719, 92.09842), (108.02219, 92.09842)), ((107.83469, 89.09842), (107.83469, 93.09842)), ((109.14719, 90.14987), (108.02219, 92.09842)), ((109.33469, 89.09842), (109.33469, 93.09842)), ((109.52219, 90.14987), (110.64719, 92.09842)), ((110.64719, 92.09842), (111.02219, 92.09842)), ((110.83469, 89.09842), (110.83469, 93.09842)), ((112.14719, 90.14987), (111.02219, 92.09842)), ((112.33469, 89.09842), (112.33469, 93.09842)), ((112.52219, 90.14987), (113.64719, 92.09842)), ((113.64719, 92.09842), (114.02219, 92.09842)), ((91.91514, 91.12742), (108.83469, 91.12742)), ((92.91514, 86.15042), (92.91514, 91.12742)), ((96.91514, 90.15042), (106.14687, 90.15042)), ((97.91514, 86.15042), (97.91514, 90.15042)), ((106.14719, 90.14987), (106.52219, 90.14987)), ((109.14719, 90.14987), (109.52219, 90.14987)), ((112.14719, 90.14987), (112.52219, 90.14987)), ((139.99997, 59.99999), (139.99997, 85.99999)), ((139.99997, 85.99999), (205.99997, 85.99999)), ((149.99997, 59.99999), (149.99997, 85.99999)), ((163.99997, 59.99999), (163.99997, 85.99999)), ((177.99997, 59.99999), (177.99997, 85.99999)), ((191.99997, 59.99999), (191.99997, 85.99999)), ((205.99997, 59.99999), (205.99997, 85.99999)), ((139.99997, 80.99999), (205.99997, 80.99999)), ((139.99997, 73.99999), (205.99997, 73.99999)), ((139.99997, 66.99999), (205.99997, 66.99999)), ((139.99997, 59.99999), (205.99997, 59.99999))]:
    msp.add_line(p, q)
for points in [[(0, 0), (594, 0), (594, 420), (0, 420)], [(20, 20), (574, 20), (574, 400), (20, 400)]]:
    msp.add_lwpolyline(points, close=True)
for radius in [15, 11.5, 11, 6.88745, 5.67502]:
    msp.add_circle((40, 175.00003), radius)
for centre, radius, start, end in [((122.97909, 190.50003), 6, 184.7801918, 270), ((138.43297, 184.75003), 0.5, 210, 270), ((159.6614, 185.00003), 1, 228.5903779, 270), ((122.97909, 159.50003), 6, 90, 175.2198082), ((138.43297, 165.25003), 0.5, 90, 150), ((159.6614, 165.00003), 1, 90, 131.4096221)]:
    msp.add_arc(centre, radius, start, end)
at = {"layer": 'CENTER'}
msp.add_line((73.99996, 174.50003), (73.99996, 175.50003), dxfattribs=at)
msp.add_circle((73.99996, 175.00003), 0.5, dxfattribs=at)
at = {"layer": 'CENTERLINE'}
msp.add_line((73.49996, 175.00003), (493.99996, 175.00003), dxfattribs=at)
at = {"layer": 'HIDDEN'}
for p, q in [((77.69996, 180.67505), (76.99996, 181.88748)), ((77.69996, 180.67505), (102.66907, 180.08969)), ((77.69996, 169.32501), (77.69996, 180.67505)), ((102.66907, 170.04785), (102.66907, 180.13554)), ((102.66907, 180.13554), (104.78483, 179.51351)), ((104.78483, 170.66989), (104.78483, 179.51351)), ((105.63101, 179.3917), (111.24493, 179.3917)), ((105.63101, 170.7917), (105.63101, 179.3917)), ((111.24493, 170.7917), (111.24493, 179.3917)), ((111.24493, 179.3917), (111.7349, 178.90173)), ((111.5825, 178.96243), (490.76571, 178.96243)), ((111.7349, 178.81003), (489.99996, 178.81003)), ((111.73496, 171.28173), (111.73496, 178.90173)), ((105.63101, 170.65415), (111.24493, 170.65415)), ((111.24493, 170.65415), (111.73496, 171.14418)), ((111.58256, 171.03763), (490.76571, 171.03763)), ((111.73496, 171.19003), (489.99996, 171.19003)), ((77.69996, 169.32501), (76.99996, 168.11258)), ((77.69996, 169.32501), (102.66907, 169.91037)), ((102.66907, 169.9103), (104.78483, 170.53234))]:
    msp.add_line(p, q, dxfattribs=at)
for centre, start, end in [((105.63101, 182.3917), 253.6167, 270), ((105.63101, 167.65415), 90, 106.3833)]:
    msp.add_arc(centre, 3, start, end, dxfattribs=at)
msp.add_point((103.04493, 180.12673), dxfattribs=at)
at = {"layer": 'PHANTOM'}
for p, q in [((122.97909, 165.50003), (122.97909, 184.50003)), ((137.99996, 184.25003), (137.99996, 166.70003)), ((159.6614, 166.00003), (159.6614, 184.00003))]:
    msp.add_line(p, q, dxfattribs=at)

# ---------------------------------------------------------------- block references
at = {"xscale": 1.800000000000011, "yscale": 1.800000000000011, "zscale": 1.8, "rotation": 90}
for p in [(87.91514, 92.09842), (92.91514, 91.12742), (97.91514, 90.15042)]:
    msp.add_blockref('_ClosedBlank', p, dxfattribs=at)

# ---------------------------------------------------------------- texts
for p in [(87.07496, 188.88128), (148.71647, 186.63128)]:
    msp.add_text('N6', height=1.5875).set_placement(p, align=Align.BOTTOM_CENTER)
at = {"attachment_point": 5}
for s, insert, char_height, width in [('\\A1;%%C19,0{\\H0.7x;\\S+0,00mm/-0,35mm;}', (151.28889, 211.07538), 2, 19.3721774), ('{\\fArial|b0|i0|c0|p34;\\Q20;\\W0.6;D1}', (148.71647, 175.00003), 6, 8.9342302), ('{\\fArial|b0|i0|c0|p34;\\Q20;\\W0.6;O}', (156.99997, 83.99999), 3, 4.4671151), ('{\\fArial|b0|i0|c0|p34;\\Q20;\\W0.6;I}', (170.99997, 83.99999), 3, 4.4671151), ('{\\fArial|b0|i0|c0|p34;\\Q20;\\W0.6;II}', (184.99997, 83.99999), 3, 4.4671151), ('{\\fArial|b0|i0|c0|p34;\\Q20;\\W0.6;III}', (198.99997, 83.99999), 3, 4.4671151), ('{\\fArial|b0|i0|c0|p34;\\Q20;\\W0.6;D1}', (144.99997, 77.49999), 3, 4.4671151), ('{\\fArial|b0|i0|c0|p34;\\Q20;\\W0.6;D2}', (144.99997, 70.49999), 3, 4.4671151), ('{\\fArial|b0|i0|c0|p34;\\Q20;\\W0.6;D3}', (144.99997, 63.49999), 3, 4.4671151)]:
    msp.add_mtext(s, dxfattribs=dict(at, insert=insert, char_height=char_height, width=width))
at = {"char_height": 1.8, "attachment_point": 5}
for s, insert in [('\\A1;{\\W0.5;18,555mm\\S+0,000mm^ -0,025mm;}', (170.99997, 77.49999)), ('\\A1;{\\W0.5;18,575mm\\S+0,00mm^ -0,02mm;}', (184.99997, 77.49999)), ('\\A1;{\\W0.5;18,635mm\\S+0,00mm^ -0,02mm;}', (198.99997, 77.49999)), ('\\A1;{\\W0.5;16,005mm\\S+0,00mm^ -0,02mm;}', (156.99997, 70.49999)), ('\\A1;{\\W0.5;16,040mm\\S+0,00mm^ -0,02mm;}', (170.99997, 70.49999)), ('\\A1;{\\W0.5;16,055mm\\S+0,000mm^ -0,015mm;}', (184.99997, 70.49999)), ('\\A1;{\\W0.5;16,12mm\\S+0,000mm^ -0,015mm;}', (198.99997, 70.49999)), ('\\A1;{\\W0.5;15,005mm\\S+0,00mm^ -0,02mm;}', (156.99997, 63.49999)), ('\\A1;{\\W0.5;15,040mm\\S+0,00mm^ -0,02mm;}', (170.99997, 63.49999)), ('\\A1;{\\W0.5;15,055mm\\S+0,000mm^ -0,015mm;}', (184.99997, 63.49999)), ('\\A1;{\\W0.5;15,12mm\\S+0,000mm^ -0,015mm;}', (198.99997, 63.49999))]:
    msp.add_mtext(s, dxfattribs=dict(at, insert=insert))
at = {"layer": 'TEXT', "color": 7, "char_height": 2, "attachment_point": 6, "rotation": 90}
for s, insert, width in [('\\A1;%%C26,0 {\\H0.7x;\\S+0,00mm/-0,25mm;}', (87.91514, 85.15042), 20.2415142), ('\\A1;%%C25,026{\\H0.7x;\\S+0,030mm/-0,014mm;}', (92.91514, 85.15042), 24.5501172), ('\\A1;%%C24,052mm', (97.91514, 85.15042), 20.2415142)]:
    msp.add_mtext(s, dxfattribs=dict(at, insert=insert, width=width))

# ---------------------------------------------------------------- dimensions: what is measured, and where the dimension line sits
for base, p1, p2, picture, middle in [((78.49996, 199.28005), (76.99996, 185.85003), (78.49996, 185.85003), '*D14', (86.29996, 199.28005)), ((76.99996, 106.89501), (491.99996, 168.75003), (76.99996, 164.15003), '*D41', (284.49996, 106.89501)), ((76.99996, 110.89501), (444.99996, 167.30003), (76.99996, 164.15003), '*D39', (260.99996, 110.89501)), ((76.99996, 114.89501), (384.99996, 167.00003), (76.99996, 164.15003), '*D38', (230.99996, 114.89501)), ((76.99996, 118.89501), (346.99996, 166.75003), (76.99996, 164.15003), '*D37', (211.99996, 118.89501)), ((76.99996, 122.89501), (285.49996, 166.01003), (76.99996, 164.15003), '*D36', (181.24996, 122.89501)), ((76.99996, 126.89501), (271.49996, 166.00003), (76.99996, 164.15003), '*D35', (174.24996, 126.89501)), ((76.99996, 130.89501), (158.99996, 165.75003), (76.99996, 164.15003), '*D34', (117.99996, 130.89501)), ((76.99996, 138.89501), (122.97909, 165.50003), (76.99996, 164.15003), '*D32', (99.98953, 138.89501)), ((76.99996, 134.89501), (137.99996, 165.50003), (76.99996, 164.15003), '*D33', (107.49996, 134.89501)), ((116.99996, 142.88501), (76.99996, 164.15003), (116.99996, 156.00003), '*D31', (96.99996, 142.88501)), ((111.99996, 146.88501), (94.99996, 163.50003), (111.99996, 163.00003), '*D43', (103.49996, 146.88501))]:
    dim = msp.add_linear_dim(base=base, p1=p1, p2=p2, dimstyle='Standard$0', override={"dimscale": 10, "dimdec": 1, "dimpost": 'mm', "dimblk1": 'ClosedBlank', "dimblk2": 'ClosedBlank', "dimsah": 1})
    dim.commit()
    dim.dimension.update_dxf_attribs({"geometry": picture, "text_midpoint": middle})
for base, line1, line2, picture, middle in [((91.71512, 193.75453), ((79.14996, 186.50003), (94.99996, 186.50003)), ((78.49996, 185.85003), (79.14996, 186.50003)), '*D15', (92.63013, 191.86621)), ((108.80319, 103.82467), ((106.52219, 90.14987), (107.64719, 92.09842)), ((106.14719, 90.14987), (105.02219, 92.09842)), '*D60', (106.33469, 104.04064))]:
    dim = msp.add_angular_dim_2l(base=base, line1=line1, line2=line2, dimstyle='Standard', override={"dimadec": 0})
    dim.commit()
    dim.dimension.update_dxf_attribs({"geometry": picture, "text_midpoint": middle, "dimtype": 162})
for base, p1, p2, picture, middle in [((51.5, 193.06911), (28.5, 175.00003), (51.5, 175.00003), '*D58', (40, 193.06911)), ((51, 156.93095), (29, 175.00003), (51, 175.00003), '*D57', (40, 156.93095))]:
    dim = msp.add_linear_dim(base=base, p1=p1, p2=p2, text='%%C<>', dimstyle='Standard$0', override={"dimscale": 9, "dimdec": 1, "dimpost": 'mm', "dimtol": 1, "dimtm": 0.35, "dimtdec": 2})
    dim.commit()
    dim.dimension.update_dxf_attribs({"geometry": picture, "text_midpoint": middle})
dim = msp.add_angular_dim_2l(base=(61.31022, 182.15795), line1=((77.69996, 180.67505), (76.99996, 181.88748)), line2=((77.69996, 169.32501), (76.99996, 168.11258)), dimstyle='Standard', override={"dimscale": 8, "dimadec": 0})
dim.commit()
dim.dimension.update_dxf_attribs({"geometry": '*D10', "text_midpoint": (60.04809, 175.00003)})
dim = msp.add_radius_dim(center=(122.97909, 190.50003), mpoint=(119.31135, 185.75159), dimstyle='Standard', override={"dimdec": 0, "dimtmove": 1})
dim.commit()
dim.dimension.update_dxf_attribs({"geometry": '*D29', "text_midpoint": (125.46811, 193.72244), "dimtype": 164})
for base, p1, p2, override, picture, middle in [((77.69996, 187.95885), (76.99996, 185.85003), (77.69996, 180.67505), {"dimscale": 5, "dimgap": 0.09, "dimdec": 2, "dimzin": 0, "dimpost": 'mm', "dimblk1": 'ClosedBlank', "dimblk2": 'ClosedBlank', "dimsah": 1, "dimtol": 1, "dimlim": 0, "dimtp": 0.1, "dimtm": 0.1, "dimtdec": 2}, '*D8', (69.35048, 187.95885)), ((113.99996, 155.64203), (111.99996, 163.00003), (113.99996, 160.00003), {"dimscale": 10, "dimdec": 1, "dimpost": 'mm', "dimblk1": 'ClosedBlank', "dimblk2": 'ClosedBlank', "dimsah": 1}, '*D42', (103.91785, 155.64203)), ((116.99996, 150.72001), (113.99996, 160.00003), (116.99996, 160.00003), {"dimscale": 10, "dimdec": 1, "dimpost": 'mm', "dimblk1": 'ClosedBlank', "dimblk2": 'ClosedBlank', "dimsah": 1}, '*D40', (106.04996, 150.72001)), ((107.83469, 99.65831), (104.83469, 93.09842), (107.83469, 93.09842), {"dimdec": 1, "dimlfac": 0.5, "dimpost": 'mm'}, '*D59', (120.24251, 99.65831))]:
    dim = msp.add_linear_dim(base=base, p1=p1, p2=p2, dimstyle='Standard$0', override=override)
    dim.commit()
    dim.dimension.update_dxf_attribs({"geometry": picture, "text_midpoint": middle, "dimtype": 160})
dim = msp.add_linear_dim(base=(71.41508, 180.67505), p1=(77.69996, 169.32501), p2=(77.69996, 180.67505), angle=90, dimstyle='Standard$0', override={"dimscale": 5, "dimdec": 2, "dimpost": 'mm', "dimtol": 1, "dimtm": 0.05, "dimtdec": 2})
dim.commit()
dim.dimension.update_dxf_attribs({"geometry": '*D9', "text_midpoint": (71.41508, 175.00003), "dimtype": 160, "text_rotation": 90})
dim = msp.add_radius_dim(center=(160.18162, 164.13052), mpoint=(159.35678, 165.9525), text='<>\\PMax', dimstyle='Standard', override={"dimscale": 10, "dimdec": 0, "dimpost": 'mm', "dimblk2": 'ClosedBlank', "dimsah": 1, "dimtmove": 1})
dim.commit()
dim.dimension.update_dxf_attribs({"geometry": '*D44', "text_midpoint": (161.06498, 162.17925), "dimtype": 164})

doc.saveas('drawing.dxf')
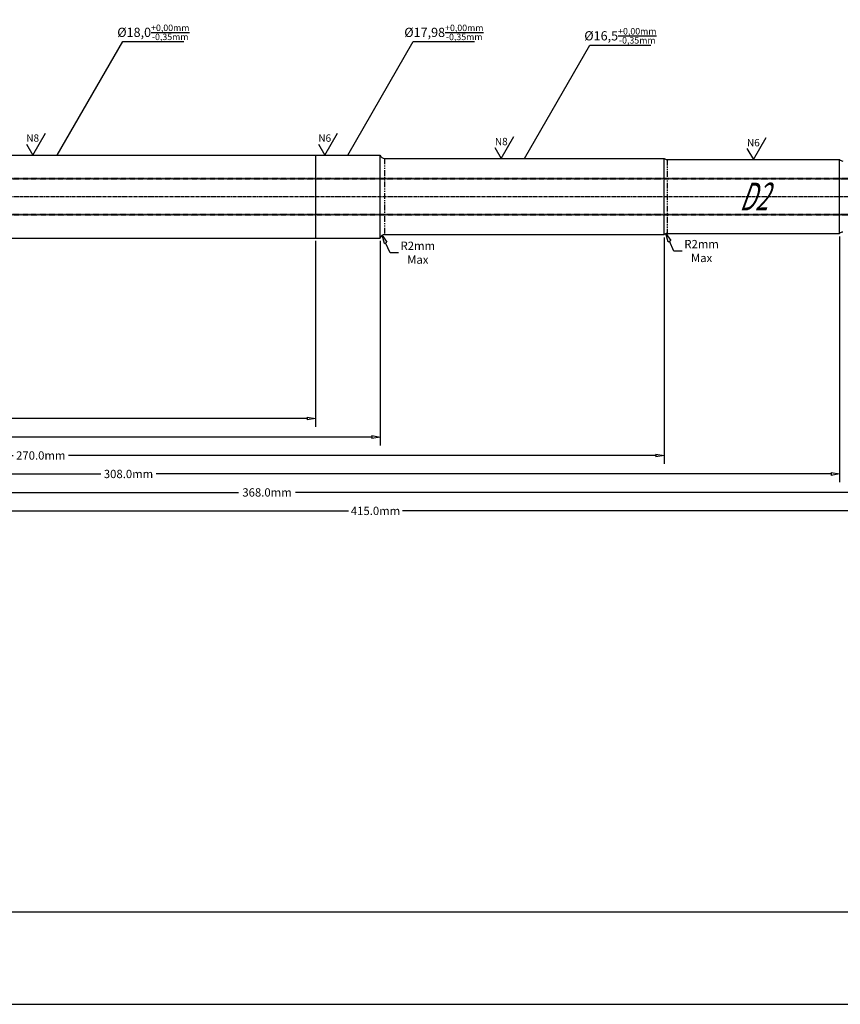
# Model space of a CAD drawing. Units: inches. Extents: x 0 to 594, y 0 to 420.
# Drawn here: x 207 to 385, y 0 to 213 of the extents above; entities that cross this region are included whole.
import ezdxf
from ezdxf.enums import TextEntityAlignment as Align

# ---------------------------------------------------------------- set-up
doc = ezdxf.new("R2010")
doc.units = ezdxf.units.IN
doc.header["$MEASUREMENT"] = 0
for name, pattern in [('CENTER2', [1.125, 0.75, -0.125, 0.125, -0.125]), ('HIDDEN2', [0.1875, 0.125, -0.0625]), ('PHANTOM', [2.5, 1.25, -0.25, 0.25, -0.25, 0.25, -0.25])]:
    doc.linetypes.add(name, pattern=pattern)
for name, color, linetype in [('CENTERLINE', 1, 'CENTER2'), ('HIDDEN', 5, 'HIDDEN2'), ('PHANTOM', 252, 'PHANTOM')]:
    doc.layers.add(name, color=color, linetype=linetype)
doc.dimstyles.get("Standard").update_dxf_attribs({"dimscale": 10, "dimtxt": 0.18, "dimasz": 0.18, "dimexe": 0.18, "dimexo": 0.0625, "dimgap": 0.09, "dimtad": 0, "dimtih": 1, "dimtoh": 1, "dimdec": 4, "dimzin": 0, "dimdsep": 46, "dimtxsty": 'Standard', "dimblk": 'CLOSEDBLANK', "dimcen": 0.09, "dimadec": 4, "dimazin": 0, "dimtfac": 1, "dimtdec": 4, "dimtofl": 0, "dimtmove": 0, "dimatfit": 3, "dimldrblk": 'CLOSEDBLANK', "dimfxl": 0, "dimtolj": 1, "dimtzin": 0, "dimarcsym": 0})
doc.dimstyles.new('Standard$0', dxfattribs={"dimscale": 10, "dimtxt": 0.18, "dimasz": 0.18, "dimexe": 0.18, "dimexo": 0.0625, "dimgap": 0.09, "dimtad": 0, "dimtih": 1, "dimtoh": 1, "dimdec": 4, "dimzin": 4, "dimdsep": 46, "dimtxsty": 'Standard', "dimblk": 'CLOSEDBLANK', "dimcen": 0.09, "dimadec": 5, "dimazin": 1, "dimtfac": 1, "dimtdec": 4, "dimtofl": 0, "dimtmove": 0, "dimatfit": 3, "dimldrblk": 'CLOSEDBLANK', "dimfxl": 0, "dimtolj": 1, "dimtzin": 0, "dimarcsym": 0})

# ---------------------------------------------------------------- blocks, each defined once
blk = doc.blocks.new('_ClosedBlank')
at = {"color": 0, "linetype": 'ByBlock', "lineweight": -2}
for p, q in [((-1, 0.17), (0, 0)), ((-1, 0.17), (-1, -0.17)), ((0, 0), (-1, -0.17))]:
    blk.add_line(p, q, dxfattribs=at)
blk = doc.blocks.new('*D35')
at = {"color": 0, "lineweight": -2}
for p, q in [((271.5, 165.38), (271.5, 125.1)), ((77, 163.53), (77, 125.1)), ((78.8, 126.9), (168.25, 126.9)), ((269.7, 126.9), (180.25, 126.9))]:
    blk.add_line(p, q, dxfattribs=at)
at = {"layer": 'Defpoints', "color": 0}
for p in [(271.5, 166), (77, 164.15), (77, 126.9)]:
    blk.add_point(p, dxfattribs=at)
at = {"color": 0, "lineweight": -2, "xscale": 1.8, "yscale": 1.8, "zscale": 1.8, "rotation": 180}
blk.add_blockref('_ClosedBlank', (77, 126.9), dxfattribs=at)
at = {"color": 0, "lineweight": -2, "xscale": 1.8, "yscale": 1.8, "zscale": 1.8}
blk.add_blockref('_ClosedBlank', (271.5, 126.9), dxfattribs=at)
at = {"color": 0, "insert": (174.25, 126.9), "char_height": 1.8, "attachment_point": 5}
blk.add_mtext('\\A1;194.5mm', dxfattribs=at)
blk = doc.blocks.new('*D36')
at = {"color": 0, "lineweight": -2}
for p, q in [((285.5, 165.39), (285.5, 121.1)), ((77, 163.53), (77, 121.1)), ((78.8, 122.9), (175.1, 122.9)), ((283.7, 122.9), (187.4, 122.9))]:
    blk.add_line(p, q, dxfattribs=at)
at = {"layer": 'Defpoints', "color": 0}
for p in [(285.5, 166.01), (77, 164.15), (77, 122.9)]:
    blk.add_point(p, dxfattribs=at)
at = {"color": 0, "lineweight": -2, "xscale": 1.8, "yscale": 1.8, "zscale": 1.8, "rotation": 180}
blk.add_blockref('_ClosedBlank', (77, 122.9), dxfattribs=at)
at = {"color": 0, "lineweight": -2, "xscale": 1.8, "yscale": 1.8, "zscale": 1.8}
blk.add_blockref('_ClosedBlank', (285.5, 122.9), dxfattribs=at)
at = {"color": 0, "insert": (181.25, 122.9), "char_height": 1.8, "attachment_point": 5}
blk.add_mtext('\\A1;208.5mm', dxfattribs=at)
blk = doc.blocks.new('*D37')
at = {"color": 0, "lineweight": -2}
for p, q in [((347, 166.13), (347, 117.1)), ((77, 163.53), (77, 117.1)), ((78.8, 118.9), (206, 118.9)), ((345.2, 118.9), (218, 118.9))]:
    blk.add_line(p, q, dxfattribs=at)
at = {"layer": 'Defpoints', "color": 0}
for p in [(347, 166.75), (77, 164.15), (77, 118.9)]:
    blk.add_point(p, dxfattribs=at)
at = {"color": 0, "lineweight": -2, "xscale": 1.8, "yscale": 1.8, "zscale": 1.8, "rotation": 180}
blk.add_blockref('_ClosedBlank', (77, 118.9), dxfattribs=at)
at = {"color": 0, "lineweight": -2, "xscale": 1.8, "yscale": 1.8, "zscale": 1.8}
blk.add_blockref('_ClosedBlank', (347, 118.9), dxfattribs=at)
at = {"color": 0, "insert": (212, 118.9), "char_height": 1.8, "attachment_point": 5}
blk.add_mtext('\\A1;270.0mm', dxfattribs=at)
blk = doc.blocks.new('*D38')
at = {"color": 0, "lineweight": -2}
for p, q in [((385, 166.38), (385, 113.1)), ((77, 163.53), (77, 113.1)), ((78.8, 114.9), (225, 114.9)), ((383.2, 114.9), (237, 114.9))]:
    blk.add_line(p, q, dxfattribs=at)
at = {"layer": 'Defpoints', "color": 0}
for p in [(385, 167), (77, 164.15), (77, 114.9)]:
    blk.add_point(p, dxfattribs=at)
at = {"color": 0, "lineweight": -2, "xscale": 1.8, "yscale": 1.8, "zscale": 1.8, "rotation": 180}
blk.add_blockref('_ClosedBlank', (77, 114.9), dxfattribs=at)
at = {"color": 0, "lineweight": -2, "xscale": 1.8, "yscale": 1.8, "zscale": 1.8}
blk.add_blockref('_ClosedBlank', (385, 114.9), dxfattribs=at)
at = {"color": 0, "insert": (231, 114.9), "char_height": 1.8, "attachment_point": 5}
blk.add_mtext('\\A1;308.0mm', dxfattribs=at)
blk = doc.blocks.new('*D39')
at = {"color": 0, "lineweight": -2}
for p, q in [((445, 166.68), (445, 109.1)), ((77, 163.53), (77, 109.1)), ((78.8, 110.9), (254.85, 110.9)), ((443.2, 110.9), (267.15, 110.9))]:
    blk.add_line(p, q, dxfattribs=at)
at = {"layer": 'Defpoints', "color": 0}
for p in [(445, 167.3), (77, 164.15), (77, 110.9)]:
    blk.add_point(p, dxfattribs=at)
at = {"color": 0, "lineweight": -2, "xscale": 1.8, "yscale": 1.8, "zscale": 1.8, "rotation": 180}
blk.add_blockref('_ClosedBlank', (77, 110.9), dxfattribs=at)
at = {"color": 0, "lineweight": -2, "xscale": 1.8, "yscale": 1.8, "zscale": 1.8}
blk.add_blockref('_ClosedBlank', (445, 110.9), dxfattribs=at)
at = {"color": 0, "insert": (261, 110.9), "char_height": 1.8, "attachment_point": 5}
blk.add_mtext('\\A1;368.0mm', dxfattribs=at)
blk = doc.blocks.new('*D41')
at = {"color": 0, "lineweight": -2}
for p, q in [((492, 168.13), (492, 105.1)), ((77, 163.53), (77, 105.1)), ((78.8, 106.9), (278.65, 106.9)), ((490.2, 106.9), (290.35, 106.9))]:
    blk.add_line(p, q, dxfattribs=at)
at = {"layer": 'Defpoints', "color": 0}
for p in [(492, 168.75), (77, 164.15), (77, 106.9)]:
    blk.add_point(p, dxfattribs=at)
at = {"color": 0, "lineweight": -2, "xscale": 1.8, "yscale": 1.8, "zscale": 1.8, "rotation": 180}
blk.add_blockref('_ClosedBlank', (77, 106.9), dxfattribs=at)
at = {"color": 0, "lineweight": -2, "xscale": 1.8, "yscale": 1.8, "zscale": 1.8}
blk.add_blockref('_ClosedBlank', (492, 106.9), dxfattribs=at)
at = {"color": 0, "insert": (284.5, 106.9), "char_height": 1.8, "attachment_point": 5}
blk.add_mtext('\\A1;415.0mm', dxfattribs=at)
blk = doc.blocks.new('*D46')
at = {"color": 0, "lineweight": -2}
for p, q in [((287.66, 162.83), (286.69, 164.97)), ((289.46, 162.83), (287.66, 162.83))]:
    blk.add_line(p, q, dxfattribs=at)
at = {"layer": 'Defpoints', "color": 0}
for p in [(285.95, 166.61), (286.77, 164.78)]:
    blk.add_point(p, dxfattribs=at)
at = {"color": 0, "lineweight": -2, "xscale": 1.8, "yscale": 1.8, "zscale": 1.8, "rotation": 114.3568269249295}
blk.add_blockref('_ClosedBlank', (285.95, 166.61), dxfattribs=at)
at = {"color": 0, "insert": (293.66, 162.83), "char_height": 1.8, "attachment_point": 5}
blk.add_mtext('\\A1;R2mm\\PMax', dxfattribs=at)
blk = doc.blocks.new('*D47')
at = {"color": 0, "lineweight": -2}
for p, q in [((349.12, 163.2), (348.16, 165.33)), ((350.92, 163.2), (349.12, 163.2))]:
    blk.add_line(p, q, dxfattribs=at)
at = {"layer": 'Defpoints', "color": 0}
for p in [(347.41, 166.97), (348.24, 165.15)]:
    blk.add_point(p, dxfattribs=at)
at = {"color": 0, "lineweight": -2, "xscale": 1.8, "yscale": 1.8, "zscale": 1.8, "rotation": 114.3568269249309}
blk.add_blockref('_ClosedBlank', (347.41, 166.97), dxfattribs=at)
at = {"color": 0, "insert": (355.12, 163.2), "char_height": 1.8, "attachment_point": 5}
blk.add_mtext('\\A1;R2mm\\PMax', dxfattribs=at)

msp = doc.modelspace()

# ---------------------------------------------------------------- linework, layer by layer
for p, q in [((215.58068, 184.00003), (229.76927, 208.57538)), ((229.76927, 208.57538), (242.99082, 208.57538)), ((278.49996, 183.99003), (292.68855, 208.56538)), ((292.68855, 208.56538), (305.9101, 208.56538)), ((316.73276, 183.25003), (330.92135, 207.82538)), ((330.92135, 207.82538), (344.14291, 207.82538)), ((210.24996, 184.00003), (212.99959, 188.76253)), ((273.49996, 183.99003), (276.24959, 188.75253)), ((311.73276, 183.25003), (314.4824, 188.01253)), ((366.33068, 183.00003), (369.08031, 187.76253)), ((208.87514, 186.38128), (210.24996, 184.00003)), ((272.12514, 186.37128), (273.49996, 183.99003)), ((310.35795, 185.63128), (311.73276, 183.25003)), ((159.6614, 184.00003), (271.49996, 184.00003)), ((271.49996, 184.00003), (271.49996, 166.00003)), ((271.49996, 183.99003), (285.49996, 183.99003)), ((285.49996, 166.01003), (285.49996, 183.99003)), ((364.95586, 185.38128), (366.33068, 183.00003)), ((286.46557, 183.25003), (346.99996, 183.25003)), ((346.99996, 166.75003), (346.99996, 183.25003)), ((347.6614, 183.00003), (384.99996, 183.00003)), ((384.99996, 167.00003), (384.99996, 183.00003)), ((384.99996, 167.00003), (384.99996, 183.00003)), ((286.46557, 166.75003), (346.99996, 166.75003)), ((347.6614, 167.00003), (384.99996, 167.00003)), ((159.6614, 166.00003), (271.49996, 166.00003)), ((271.49996, 166.01003), (285.49996, 166.01003))]:
    msp.add_line(p, q)
for points in [[(0, 0), (594, 0), (594, 420), (0, 420)], [(20, 20), (574, 20), (574, 400), (20, 400)]]:
    msp.add_lwpolyline(points, close=True)
for centre, start, end in [((286.46557, 184.25003), 195.0700621, 270), ((347.6614, 184.00003), 228.5903779, 270), ((385.7141, 183.70003), 224.427004, 270), ((286.46557, 165.75003), 90, 164.9299379), ((347.6614, 166.00003), 90, 131.4096221), ((385.7141, 166.30003), 90, 135.572996)]:
    msp.add_arc(centre, 1, start, end)
at = {"layer": 'CENTERLINE'}
msp.add_line((73.49996, 175.00003), (493.99996, 175.00003), dxfattribs=at)
at = {"layer": 'HIDDEN'}
for p, q in [((111.5825, 178.96243), (490.76571, 178.96243)), ((111.7349, 178.81003), (489.99996, 178.81003)), ((111.58256, 171.03763), (490.76571, 171.03763)), ((111.73496, 171.19003), (489.99996, 171.19003))]:
    msp.add_line(p, q, dxfattribs=at)
at = {"layer": 'PHANTOM'}
for p, q in [((286.46557, 183.25003), (286.46557, 166.75003)), ((347.6614, 183.00003), (347.6614, 167.00003))]:
    msp.add_line(p, q, dxfattribs=at)

# ---------------------------------------------------------------- texts
for s, p in [('N8', (210.24996, 186.38128)), ('N6', (273.49996, 186.37128)), ('N8', (311.73276, 185.63128)), ('N6', (366.33068, 185.38128))]:
    msp.add_text(s, height=1.5875).set_placement(p, align=Align.BOTTOM_CENTER)
at = {"attachment_point": 5}
for s, insert, char_height, width in [('\\A1;%%C18,0{\\H0.7x;\\S+0,00mm/-0,35mm;}', (236.38004, 210.57538), 2, 19.3721774), ('\\A1;%%C17,98{\\H0.7x;\\S+0,00mm/-0,35mm;}', (299.29932, 210.56538), 2, 19.3721774), ('\\A1;%%C16,5{\\H0.7x;\\S+0,00mm/-0,35mm;}', (337.53213, 209.82538), 2, 19.3721774), ('{\\fArial|b0|i0|c0|p34;\\Q20;\\W0.6;D2}', (366.33068, 175.00003), 6, 8.9342302)]:
    msp.add_mtext(s, dxfattribs=dict(at, insert=insert, char_height=char_height, width=width))

# ---------------------------------------------------------------- dimensions: what is measured, and where the dimension line sits
for base, p1, picture, middle in [((76.99996, 106.89501), (491.99996, 168.75003), '*D41', (284.49996, 106.89501)), ((76.99996, 110.89501), (444.99996, 167.30003), '*D39', (260.99996, 110.89501)), ((76.99996, 114.89501), (384.99996, 167.00003), '*D38', (230.99996, 114.89501)), ((76.99996, 118.89501), (346.99996, 166.75003), '*D37', (211.99996, 118.89501)), ((76.99996, 122.89501), (285.49996, 166.01003), '*D36', (181.24996, 122.89501)), ((76.99996, 126.89501), (271.49996, 166.00003), '*D35', (174.24996, 126.89501))]:
    dim = msp.add_linear_dim(base=base, p1=p1, p2=(76.99996, 164.15003), dimstyle='Standard$0', override={"dimscale": 10, "dimdec": 1, "dimpost": 'mm', "dimblk1": 'ClosedBlank', "dimblk2": 'ClosedBlank', "dimsah": 1})
    dim.commit()
    dim.dimension.update_dxf_attribs({"geometry": picture, "text_midpoint": middle})
for center, mpoint, picture, middle in [((286.77464, 164.78477), (285.9498, 166.60676), '*D46', (287.658, 162.8335)), ((348.23816, 165.14678), (347.41333, 166.96877), '*D47', (349.12153, 163.19551))]:
    dim = msp.add_radius_dim(center=center, mpoint=mpoint, text='<>\\PMax', dimstyle='Standard', override={"dimscale": 10, "dimdec": 0, "dimpost": 'mm', "dimblk2": 'ClosedBlank', "dimsah": 1, "dimtmove": 1})
    dim.commit()
    dim.dimension.update_dxf_attribs({"geometry": picture, "text_midpoint": middle, "dimtype": 164})

doc.saveas('drawing.dxf')
